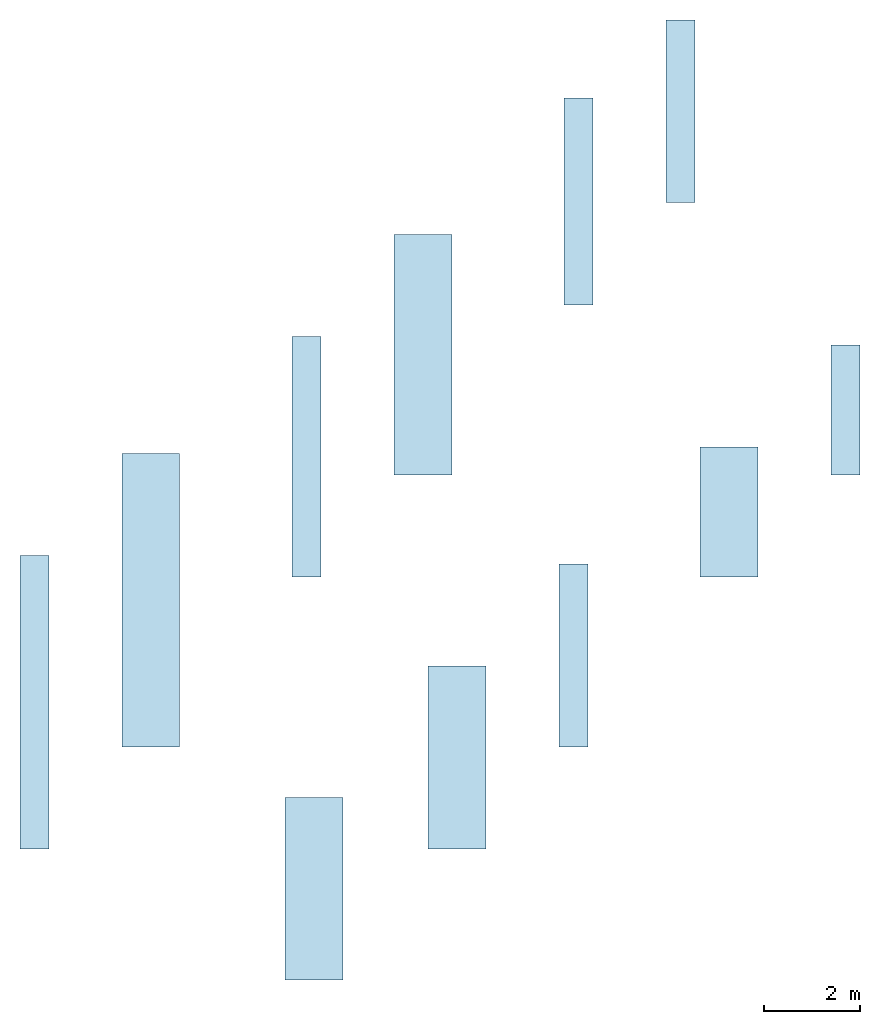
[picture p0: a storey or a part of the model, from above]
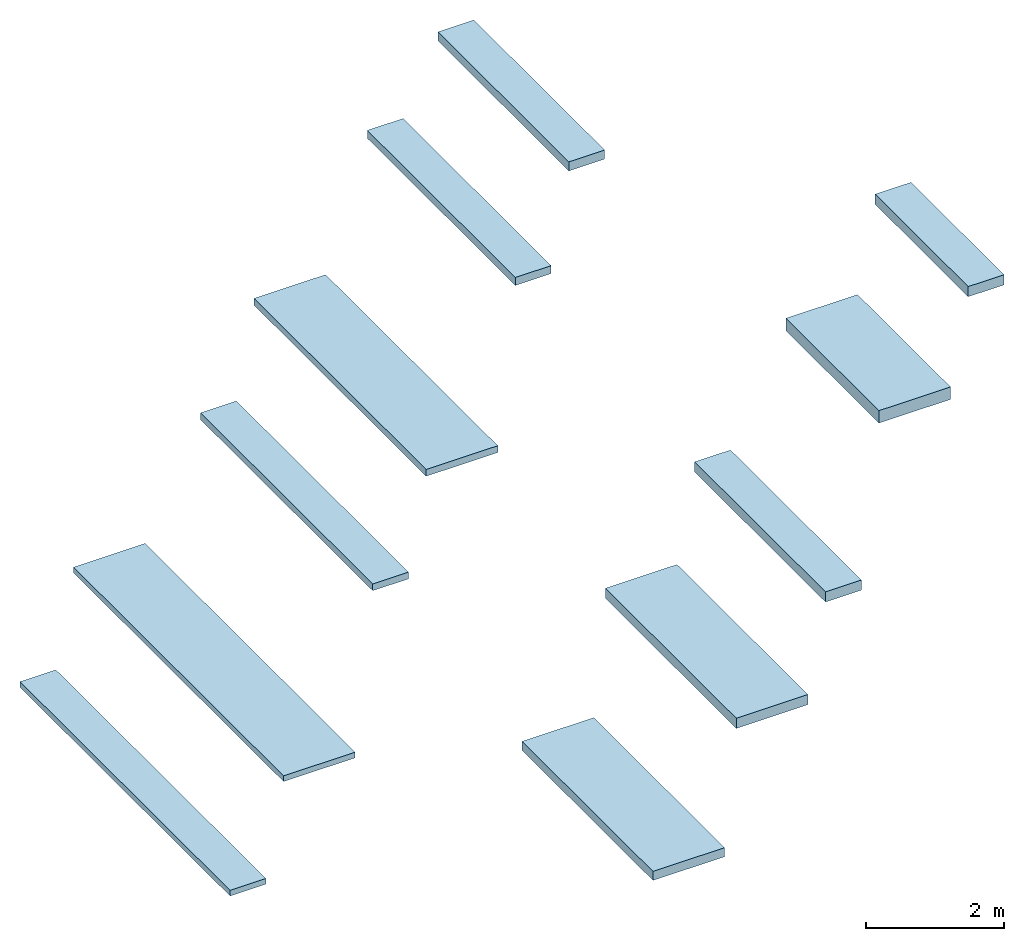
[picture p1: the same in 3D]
Properties of the parts of a building model (IFC2X3)

# File
Description: ViewDefinition [CoordinationView_V2.0, QuantityTakeOffAddOnView]
Time: 2021-05-19T20:16:23
Written by: The EXPRESS Data Manager Version 5.02.0100.07 : 28 Aug 2013
Made in: 20190108_1515(x64) - Exporter 19.1.0.0 - Alternate UI 19.1.0.0
Comment: STEP Physical File produced by: The EXPRESS Data Manager Version 5.02.0100.07 : 28 Aug 2013 * Module: EDMstepFileFactory/EDMstandAlone * Creation date: Wed May 19 20:16:23 2021 * Host: lt-026 * Database: C:\Users\WF2BF~1.POE\AppData\Local\Temp\{DC780830-4905-4681-B3EC-D57499B1AC45}\ifc * Database version: 5507 * Database creation date: Wed May 19 20:16:22 2021 * Schema: IFC2X3 * Model: DataRepository.ifc * Model creation date: Wed May 19 20:16:23 2021 * Header model: DataRepository.ifc_HeaderModel * Header model creation date: Wed May 19 20:16:23 2021 * EDMuser: sdai-user * EDMgroup: sdai-group * License ID and type: 5605 : Permanent license. Expiry date: * EDMstepFileFactory options: 020000

# IfcSite, Default
RefLatitude: 42, 24, 53, 508911; RefLongitude: -71, -15, -29, -58837; RefElevation: 0 mm
Other - Category: Project Information

# IfcBuilding
Pset_BuildingCommon - NumberOfStoreys: 1
Pset_ProductRequirements - Category: Project Information; sets with these values: 2

# IfcBuildingStorey: Level:Level 1, Level 1
LongName: Level 1; Elevation: 0 mm
Pset_AirSideSystemInformation - Name: Level 1
Pset_ProductRequirements - Name: Level 1; Category: Levels
Constraints - Elevation: 0 mm
Dimensions - Computation Height: 0 mm
Identity Data - Building Story: yes; Name: Level 1; Structural: no
Other - Category: Levels; Family: Level: Level 1; Family and Type: Level: Level 1; Type: Level: Level 1; Type Id: Level: Level 1
Constraints(Type) - Elevation Base: Project Base Point
Graphics(Type) - Color: 0; Line Pattern: Solid; Line Weight: 1; Symbol at End 1 Default: no; Symbol at End 2 Default: yes
Identity Data(Type) - Type Name: Level 1
Other(Type) - Category: Levels; Family Name: Level

# IfcRoof: Basic Roof:NLRS_27_RO_Mineral Wool 34 Alu Plus_100x1200x6100mm, Basic Roof:NLRS_27_RO_Mineral Wool 34 Alu Plus_100x1200x6100mm:4963
In: Level 1
Classification: 27 Daken (Uniformat)
Pset_ElementShading - Roughness: 304.8 mm
Pset_ManufacturerTypeInformation - Manufacturer: Knauf Insulation B.V.
Pset_ProductRequirements - Category: Roofs
Pset_QuantityTakeOff - Reference: NLRS_27_RO_Mineral Wool 34 Alu Plus_100x1200x6100mm
Pset_RoofCommon - IsExternal: yes; Reference: NLRS_27_RO_Mineral Wool 34 Alu Plus_100x1200x6100mm; ProjectedArea: 7.32 m2; TotalArea: 7.32 m2
Constraints - Base Level: Level: Level 1; Base Offset From Level: 0 mm; Cutoff Offset: 0 mm; Related to Mass: no; Room Bounding: yes
Construction - Fascia Depth: 0 mm; Rafter Cut: Plumb Cut; Maximum Ridge Height: 100 mm
Dimensions - Area: 7.32 m2; Thickness: 100 mm; Volume: 0.732 m3
Other - Category: Roofs; Family: Basic Roof: NLRS_27_RO_Mineral Wool 34 Alu Plus_100x1200x6100mm; Family and Type: Basic Roof: NLRS_27_RO_Mineral Wool 34 Alu Plus_100x1200x6100mm; Type: Basic Roof: NLRS_27_RO_Mineral Wool 34 Alu Plus_100x1200x6100mm; Type Id: Basic Roof: NLRS_27_RO_Mineral Wool 34 Alu Plus_100x1200x6100mm
Phasing - Phase Created: New Construction
Analytical Properties(Type) - Roughness: 1; Thermal mass: 0; Absorptance: 0.1; Heat Transfer Coefficient (U): 0.34; Thermal Resistance (R): 2.94118
Construction(Type) - Default Thickness: 100 mm
Graphics(Type) - Coarse Scale Fill Color: 0
Identity Data(Type) - Type Image: Raster image: MW 34 Alu Plus .jpg (2); Assembly Code: 27; Assembly Description: Daken; Description: Mineral Wool 34 Alu Plus - 100mm; Manufacturer: Knauf Insulation B.V.; Model: Mineral Wool 34 Alu Plus is een minerale woldeken met ECOSE® Technology, bekleed met een dampdichte Aluminium folie; Type Name: NLRS_27_RO_Mineral Wool 34 Alu Plus_100x1200x6100mm; URL: www.knaufinsulation.nl
Other(Type) - Category: Roofs; Family Name: Basic Roof

# IfcRoof: Basic Roof:NLRS_27_RO_Mineral Wool 34 Alu Plus_100x600x6100mm, Basic Roof:NLRS_27_RO_Mineral Wool 34 Alu Plus_100x600x6100mm:4934
In: Level 1
Classification: 27 Daken (Uniformat)
Pset_ElementShading - Roughness: 304.8 mm
Pset_ManufacturerTypeInformation - Manufacturer: Knauf Insulation B.V.
Pset_ProductRequirements - Category: Roofs
Pset_QuantityTakeOff - Reference: NLRS_27_RO_Mineral Wool 34 Alu Plus_100x600x6100mm
Pset_RoofCommon - Reference: NLRS_27_RO_Mineral Wool 34 Alu Plus_100x600x6100mm; IsExternal: yes; ProjectedArea: 3.66 m2; TotalArea: 3.66 m2
Constraints - Base Level: Level: Level 1; Base Offset From Level: 0 mm; Cutoff Offset: 0 mm; Related to Mass: no; Room Bounding: yes
Construction - Fascia Depth: 0 mm; Maximum Ridge Height: 100 mm; Rafter Cut: Plumb Cut
Dimensions - Area: 3.66 m2; Thickness: 100 mm; Volume: 0.366 m3
Other - Category: Roofs; Family: Basic Roof: NLRS_27_RO_Mineral Wool 34 Alu Plus_100x600x6100mm; Family and Type: Basic Roof: NLRS_27_RO_Mineral Wool 34 Alu Plus_100x600x6100mm; Type: Basic Roof: NLRS_27_RO_Mineral Wool 34 Alu Plus_100x600x6100mm; Type Id: Basic Roof: NLRS_27_RO_Mineral Wool 34 Alu Plus_100x600x6100mm
Phasing - Phase Created: New Construction
Analytical Properties(Type) - Absorptance: 0.1; Heat Transfer Coefficient (U): 0.34; Roughness: 1; Thermal mass: 0; Thermal Resistance (R): 2.94118
Construction(Type) - Default Thickness: 100 mm
Graphics(Type) - Coarse Scale Fill Color: 0
Identity Data(Type) - Assembly Code: 27; Assembly Description: Daken; Description: Mineral Wool 34 Alu Plus - 100mm; Manufacturer: Knauf Insulation B.V.; Model: Mineral Wool 34 Alu Plus is een minerale woldeken met ECOSE® Technology, bekleed met een dampdichte Aluminium folie; Type Image: Raster image: MW 34 Alu Plus .jpg (2); Type Name: NLRS_27_RO_Mineral Wool 34 Alu Plus_100x600x6100mm; URL: www.knaufinsulation.nl
Other(Type) - Category: Roofs; Family Name: Basic Roof

# IfcRoof: Basic Roof:NLRS_27_RO_Mineral Wool 34 Alu Plus_120x1200x5000mm, Basic Roof:NLRS_27_RO_Mineral Wool 34 Alu Plus_120x1200x5000mm:5133
In: Level 1
Classification: 27 Daken (Uniformat)
Pset_ElementShading - Roughness: 304.8 mm
Pset_ManufacturerTypeInformation - Manufacturer: Knauf Insulation B.V.
Pset_ProductRequirements - Category: Roofs
Pset_QuantityTakeOff - Reference: NLRS_27_RO_Mineral Wool 34 Alu Plus_120x1200x5000mm
Pset_RoofCommon - IsExternal: yes; Reference: NLRS_27_RO_Mineral Wool 34 Alu Plus_120x1200x5000mm; ProjectedArea: 6 m2; TotalArea: 6 m2
Constraints - Base Level: Level: Level 1; Base Offset From Level: 0 mm; Cutoff Offset: 0 mm; Related to Mass: no; Room Bounding: yes
Construction - Fascia Depth: 0 mm; Rafter Cut: Plumb Cut; Maximum Ridge Height: 120 mm
Dimensions - Area: 6 m2; Thickness: 120 mm; Volume: 0.72 m3
Other - Category: Roofs; Family: Basic Roof: NLRS_27_RO_Mineral Wool 34 Alu Plus_120x1200x5000mm; Family and Type: Basic Roof: NLRS_27_RO_Mineral Wool 34 Alu Plus_120x1200x5000mm; Type: Basic Roof: NLRS_27_RO_Mineral Wool 34 Alu Plus_120x1200x5000mm; Type Id: Basic Roof: NLRS_27_RO_Mineral Wool 34 Alu Plus_120x1200x5000mm
Phasing - Phase Created: New Construction
Analytical Properties(Type) - Roughness: 1; Thermal mass: 0; Absorptance: 0.1; Heat Transfer Coefficient (U): 0.283333; Thermal Resistance (R): 3.52941
Construction(Type) - Default Thickness: 120 mm
Graphics(Type) - Coarse Scale Fill Color: 0
Identity Data(Type) - Type Image: Raster image: MW 34 Alu Plus .jpg (2); Assembly Code: 27; Assembly Description: Daken; Description: Mineral Wool 34 Alu Plus - 120mm; Manufacturer: Knauf Insulation B.V.; Model: Mineral Wool 34 Alu Plus is een minerale woldeken met ECOSE® Technology, bekleed met een dampdichte Aluminium folie; Type Name: NLRS_27_RO_Mineral Wool 34 Alu Plus_120x1200x5000mm; URL: www.knaufinsulation.nl
Other(Type) - Category: Roofs; Family Name: Basic Roof

# IfcRoof: Basic Roof:NLRS_27_RO_Mineral Wool 34 Alu Plus_120x600x5000mm, Basic Roof:NLRS_27_RO_Mineral Wool 34 Alu Plus_120x600x5000mm:5124
In: Level 1
Classification: 27 Daken (Uniformat)
Pset_ElementShading - Roughness: 304.8 mm
Pset_ManufacturerTypeInformation - Manufacturer: Knauf Insulation B.V.
Pset_ProductRequirements - Category: Roofs
Pset_QuantityTakeOff - Reference: NLRS_27_RO_Mineral Wool 34 Alu Plus_120x600x5000mm
Pset_RoofCommon - IsExternal: yes; Reference: NLRS_27_RO_Mineral Wool 34 Alu Plus_120x600x5000mm; ProjectedArea: 3 m2; TotalArea: 3 m2
Constraints - Base Level: Level: Level 1; Base Offset From Level: 0 mm; Cutoff Offset: 0 mm; Related to Mass: no; Room Bounding: yes
Construction - Fascia Depth: 0 mm; Rafter Cut: Plumb Cut; Maximum Ridge Height: 120 mm
Dimensions - Area: 3 m2; Thickness: 120 mm; Volume: 0.36 m3
Other - Category: Roofs; Family: Basic Roof: NLRS_27_RO_Mineral Wool 34 Alu Plus_120x600x5000mm; Family and Type: Basic Roof: NLRS_27_RO_Mineral Wool 34 Alu Plus_120x600x5000mm; Type: Basic Roof: NLRS_27_RO_Mineral Wool 34 Alu Plus_120x600x5000mm; Type Id: Basic Roof: NLRS_27_RO_Mineral Wool 34 Alu Plus_120x600x5000mm
Phasing - Phase Created: New Construction
Analytical Properties(Type) - Roughness: 1; Thermal mass: 0; Absorptance: 0.1; Heat Transfer Coefficient (U): 0.283333; Thermal Resistance (R): 3.52941
Construction(Type) - Default Thickness: 120 mm
Graphics(Type) - Coarse Scale Fill Color: 0
Identity Data(Type) - Type Image: Raster image: MW 34 Alu Plus .jpg (2); Assembly Code: 27; Assembly Description: Daken; Description: Mineral Wool 34 Alu Plus - 120mm; Manufacturer: Knauf Insulation B.V.; Model: Mineral Wool 34 Alu Plus is een minerale woldeken met ECOSE® Technology, bekleed met een dampdichte Aluminium folie; Type Name: NLRS_27_RO_Mineral Wool 34 Alu Plus_120x600x5000mm; URL: www.knaufinsulation.nl
Other(Type) - Category: Roofs; Family Name: Basic Roof

# IfcRoof: Basic Roof:NLRS_27_RO_Mineral Wool 34 Alu Plus_140x600x4300mm, Basic Roof:NLRS_27_RO_Mineral Wool 34 Alu Plus_140x600x4300mm:5226
In: Level 1
Classification: 27 Daken (Uniformat)
Pset_ElementShading - Roughness: 304.8 mm
Pset_ManufacturerTypeInformation - Manufacturer: Knauf Insulation B.V.
Pset_ProductRequirements - Category: Roofs
Pset_QuantityTakeOff - Reference: NLRS_27_RO_Mineral Wool 34 Alu Plus_140x600x4300mm
Pset_RoofCommon - IsExternal: yes; Reference: NLRS_27_RO_Mineral Wool 34 Alu Plus_140x600x4300mm; ProjectedArea: 2.58 m2; TotalArea: 2.58 m2
Constraints - Base Level: Level: Level 1; Base Offset From Level: 0 mm; Cutoff Offset: 0 mm; Related to Mass: no; Room Bounding: yes
Construction - Fascia Depth: 0 mm; Rafter Cut: Plumb Cut; Maximum Ridge Height: 140 mm
Dimensions - Area: 2.58 m2; Thickness: 140 mm; Volume: 0.3612 m3
Other - Category: Roofs; Family: Basic Roof: NLRS_27_RO_Mineral Wool 34 Alu Plus_140x600x4300mm; Family and Type: Basic Roof: NLRS_27_RO_Mineral Wool 34 Alu Plus_140x600x4300mm; Type: Basic Roof: NLRS_27_RO_Mineral Wool 34 Alu Plus_140x600x4300mm; Type Id: Basic Roof: NLRS_27_RO_Mineral Wool 34 Alu Plus_140x600x4300mm
Phasing - Phase Created: New Construction
Analytical Properties(Type) - Roughness: 1; Thermal mass: 0; Absorptance: 0.1; Heat Transfer Coefficient (U): 0.242857; Thermal Resistance (R): 4.11765
Construction(Type) - Default Thickness: 140 mm
Graphics(Type) - Coarse Scale Fill Color: 0
Identity Data(Type) - Type Image: Raster image: MW 34 Alu Plus .jpg (2); Assembly Code: 27; Assembly Description: Daken; Description: Mineral Wool 34 Alu Plus - 140mm; Manufacturer: Knauf Insulation B.V.; Model: Mineral Wool 34 Alu Plus is een minerale woldeken met ECOSE® Technology, bekleed met een dampdichte Aluminium folie; Type Name: NLRS_27_RO_Mineral Wool 34 Alu Plus_140x600x4300mm; URL: www.knaufinsulation.nl
Other(Type) - Category: Roofs; Family Name: Basic Roof

# IfcRoof: Basic Roof:NLRS_27_RO_Mineral Wool 34 Alu Plus_160x1200x3800mm, Basic Roof:NLRS_27_RO_Mineral Wool 34 Alu Plus_160x1200x3800mm:6059
In: Level 1
Classification: 27 Daken (Uniformat)
Pset_ElementShading - Roughness: 304.8 mm
Pset_ManufacturerTypeInformation - Manufacturer: Knauf Insulation B.V.
Pset_ProductRequirements - Category: Roofs
Pset_QuantityTakeOff - Reference: NLRS_27_RO_Mineral Wool 34 Alu Plus_160x1200x3800mm
Pset_RoofCommon - IsExternal: yes; Reference: NLRS_27_RO_Mineral Wool 34 Alu Plus_160x1200x3800mm; ProjectedArea: 4.56 m2; TotalArea: 4.56 m2
Constraints - Base Level: Level: Level 1; Base Offset From Level: 0 mm; Cutoff Offset: 0 mm; Related to Mass: no; Room Bounding: yes
Construction - Fascia Depth: 0 mm; Rafter Cut: Plumb Cut; Maximum Ridge Height: 160 mm
Dimensions - Area: 4.56 m2; Thickness: 160 mm; Volume: 0.7296 m3
Other - Category: Roofs; Family: Basic Roof: NLRS_27_RO_Mineral Wool 34 Alu Plus_160x1200x3800mm; Family and Type: Basic Roof: NLRS_27_RO_Mineral Wool 34 Alu Plus_160x1200x3800mm; Type: Basic Roof: NLRS_27_RO_Mineral Wool 34 Alu Plus_160x1200x3800mm; Type Id: Basic Roof: NLRS_27_RO_Mineral Wool 34 Alu Plus_160x1200x3800mm
Phasing - Phase Created: New Construction
Analytical Properties(Type) - Roughness: 1; Thermal mass: 0; Absorptance: 0.1; Heat Transfer Coefficient (U): 0.2125; Thermal Resistance (R): 4.70588
Construction(Type) - Default Thickness: 160 mm
Graphics(Type) - Coarse Scale Fill Color: 0
Identity Data(Type) - Type Image: Raster image: MW 34 Alu Plus .jpg (2); Assembly Code: 27; Assembly Description: Daken; Description: Mineral Wool 34 Alu Plus - 160mm; Manufacturer: Knauf Insulation B.V.; Model: Mineral Wool 34 Alu Plus is een minerale woldeken met ECOSE® Technology, bekleed met een dampdichte Aluminium folie; Type Name: NLRS_27_RO_Mineral Wool 34 Alu Plus_160x1200x3800mm; URL: www.knaufinsulation.nl
Other(Type) - Category: Roofs; Family Name: Basic Roof

# IfcRoof: Basic Roof:NLRS_27_RO_Mineral Wool 34 Alu Plus_160x600x3800mm, Basic Roof:NLRS_27_RO_Mineral Wool 34 Alu Plus_160x600x3800mm:5233
In: Level 1
Classification: 27 Daken (Uniformat)
Pset_ElementShading - Roughness: 304.8 mm
Pset_ManufacturerTypeInformation - Manufacturer: Knauf Insulation B.V.
Pset_ProductRequirements - Category: Roofs
Pset_QuantityTakeOff - Reference: NLRS_27_RO_Mineral Wool 34 Alu Plus_160x600x3800mm
Pset_RoofCommon - IsExternal: yes; Reference: NLRS_27_RO_Mineral Wool 34 Alu Plus_160x600x3800mm; ProjectedArea: 2.28 m2; TotalArea: 2.28 m2
Constraints - Base Level: Level: Level 1; Base Offset From Level: 0 mm; Cutoff Offset: 0 mm; Related to Mass: no; Room Bounding: yes
Construction - Fascia Depth: 0 mm; Rafter Cut: Plumb Cut; Maximum Ridge Height: 160 mm
Dimensions - Area: 2.28 m2; Thickness: 160 mm; Volume: 0.3648 m3
Other - Category: Roofs; Family: Basic Roof: NLRS_27_RO_Mineral Wool 34 Alu Plus_160x600x3800mm; Family and Type: Basic Roof: NLRS_27_RO_Mineral Wool 34 Alu Plus_160x600x3800mm; Type: Basic Roof: NLRS_27_RO_Mineral Wool 34 Alu Plus_160x600x3800mm; Type Id: Basic Roof: NLRS_27_RO_Mineral Wool 34 Alu Plus_160x600x3800mm
Phasing - Phase Created: New Construction
Analytical Properties(Type) - Roughness: 1; Thermal mass: 0; Absorptance: 0.1; Heat Transfer Coefficient (U): 0.2125; Thermal Resistance (R): 4.70588
Construction(Type) - Default Thickness: 160 mm
Graphics(Type) - Coarse Scale Fill Color: 0
Identity Data(Type) - Type Image: Raster image: MW 34 Alu Plus .jpg (2); Assembly Code: 27; Assembly Description: Daken; Description: Mineral Wool 34 Alu Plus - 160mm; Manufacturer: Knauf Insulation B.V.; Model: Mineral Wool 34 Alu Plus is een minerale woldeken met ECOSE® Technology, bekleed met een dampdichte Aluminium folie; Type Name: NLRS_27_RO_Mineral Wool 34 Alu Plus_160x600x3800mm; URL: www.knaufinsulation.nl
Other(Type) - Category: Roofs; Family Name: Basic Roof

# IfcRoof: Basic Roof:NLRS_27_RO_Mineral Wool 34 Alu Plus_180x1200x3400mm, Basic Roof:NLRS_27_RO_Mineral Wool 34 Alu Plus_180x1200x3400mm:5939
In: Level 1
Classification: 27 Daken (Uniformat)
Pset_ElementShading - Roughness: 304.8 mm
Pset_ManufacturerTypeInformation - Manufacturer: Knauf Insulation B.V.
Pset_ProductRequirements - Category: Roofs
Pset_QuantityTakeOff - Reference: NLRS_27_RO_Mineral Wool 34 Alu Plus_180x1200x3400mm
Pset_RoofCommon - IsExternal: yes; Reference: NLRS_27_RO_Mineral Wool 34 Alu Plus_180x1200x3400mm; ProjectedArea: 4.56 m2; TotalArea: 4.56 m2
Constraints - Base Level: Level: Level 1; Base Offset From Level: 0 mm; Cutoff Offset: 0 mm; Related to Mass: no; Room Bounding: yes
Construction - Fascia Depth: 0 mm; Rafter Cut: Plumb Cut; Maximum Ridge Height: 180 mm
Dimensions - Area: 4.56 m2; Thickness: 180 mm; Volume: 0.8208 m3
Other - Category: Roofs; Family: Basic Roof: NLRS_27_RO_Mineral Wool 34 Alu Plus_180x1200x3400mm; Family and Type: Basic Roof: NLRS_27_RO_Mineral Wool 34 Alu Plus_180x1200x3400mm; Type: Basic Roof: NLRS_27_RO_Mineral Wool 34 Alu Plus_180x1200x3400mm; Type Id: Basic Roof: NLRS_27_RO_Mineral Wool 34 Alu Plus_180x1200x3400mm
Phasing - Phase Created: New Construction
Analytical Properties(Type) - Roughness: 1; Thermal mass: 0; Absorptance: 0.1; Heat Transfer Coefficient (U): 0.188889; Thermal Resistance (R): 5.29412
Construction(Type) - Default Thickness: 180 mm
Graphics(Type) - Coarse Scale Fill Color: 0
Identity Data(Type) - Type Image: Raster image: MW 34 Alu Plus .jpg (2); Assembly Code: 27; Assembly Description: Daken; Description: Mineral Wool 34 Alu Plus - 180mm; Manufacturer: Knauf Insulation B.V.; Model: Mineral Wool 34 Alu Plus is een minerale woldeken met ECOSE® Technology, bekleed met een dampdichte Aluminium folie; Type Name: NLRS_27_RO_Mineral Wool 34 Alu Plus_180x1200x3400mm; URL: www.knaufinsulation.nl
Other(Type) - Category: Roofs; Family Name: Basic Roof

# IfcRoof: Basic Roof:NLRS_27_RO_Mineral Wool 34 Alu Plus_180x600x3400mm, Basic Roof:NLRS_27_RO_Mineral Wool 34 Alu Plus_180x600x3400mm:6156
In: Level 1
Classification: 27 Daken (Uniformat)
Pset_ElementShading - Roughness: 304.8 mm
Pset_ManufacturerTypeInformation - Manufacturer: Knauf Insulation B.V.
Pset_ProductRequirements - Category: Roofs
Pset_QuantityTakeOff - Reference: NLRS_27_RO_Mineral Wool 34 Alu Plus_180x600x3400mm
Pset_RoofCommon - IsExternal: yes; Reference: NLRS_27_RO_Mineral Wool 34 Alu Plus_180x600x3400mm; ProjectedArea: 2.28 m2; TotalArea: 2.28 m2
Constraints - Base Level: Level: Level 1; Base Offset From Level: 0 mm; Cutoff Offset: 0 mm; Related to Mass: no; Room Bounding: yes
Construction - Fascia Depth: 0 mm; Rafter Cut: Plumb Cut; Maximum Ridge Height: 180 mm
Dimensions - Area: 2.28 m2; Thickness: 180 mm; Volume: 0.4104 m3
Other - Category: Roofs; Family: Basic Roof: NLRS_27_RO_Mineral Wool 34 Alu Plus_180x600x3400mm; Family and Type: Basic Roof: NLRS_27_RO_Mineral Wool 34 Alu Plus_180x600x3400mm; Type: Basic Roof: NLRS_27_RO_Mineral Wool 34 Alu Plus_180x600x3400mm; Type Id: Basic Roof: NLRS_27_RO_Mineral Wool 34 Alu Plus_180x600x3400mm
Phasing - Phase Created: New Construction
Analytical Properties(Type) - Roughness: 1; Thermal mass: 0; Absorptance: 0.1; Heat Transfer Coefficient (U): 0.188889; Thermal Resistance (R): 5.29412
Construction(Type) - Default Thickness: 180 mm
Graphics(Type) - Coarse Scale Fill Color: 0
Identity Data(Type) - Type Image: Raster image: MW 34 Alu Plus .jpg (2); Assembly Code: 27; Assembly Description: Daken; Description: Mineral Wool 34 Alu Plus - 180mm; Manufacturer: Knauf Insulation B.V.; Model: Mineral Wool 34 Alu Plus is een minerale woldeken met ECOSE® Technology, bekleed met een dampdichte Aluminium folie; Type Name: NLRS_27_RO_Mineral Wool 34 Alu Plus_180x600x3400mm; URL: www.knaufinsulation.nl
Other(Type) - Category: Roofs; Family Name: Basic Roof

# IfcRoof: Basic Roof:NLRS_27_RO_Mineral Wool 34 Alu Plus_220x1200x2700mm, Basic Roof:NLRS_27_RO_Mineral Wool 34 Alu Plus_220x1200x2700mm:6230
In: Level 1
Classification: 27 Daken (Uniformat)
Pset_ElementShading - Roughness: 304.8 mm
Pset_ManufacturerTypeInformation - Manufacturer: Knauf Insulation B.V.
Pset_ProductRequirements - Category: Roofs
Pset_QuantityTakeOff - Reference: NLRS_27_RO_Mineral Wool 34 Alu Plus_220x1200x2700mm
Pset_RoofCommon - IsExternal: yes; Reference: NLRS_27_RO_Mineral Wool 34 Alu Plus_220x1200x2700mm; ProjectedArea: 3.24 m2; TotalArea: 3.24 m2
Constraints - Base Level: Level: Level 1; Base Offset From Level: 0 mm; Cutoff Offset: 0 mm; Related to Mass: no; Room Bounding: yes
Construction - Fascia Depth: 0 mm; Rafter Cut: Plumb Cut; Maximum Ridge Height: 220 mm
Dimensions - Area: 3.24 m2; Thickness: 220 mm; Volume: 0.7128 m3
Other - Category: Roofs; Family: Basic Roof: NLRS_27_RO_Mineral Wool 34 Alu Plus_220x1200x2700mm; Family and Type: Basic Roof: NLRS_27_RO_Mineral Wool 34 Alu Plus_220x1200x2700mm; Type: Basic Roof: NLRS_27_RO_Mineral Wool 34 Alu Plus_220x1200x2700mm; Type Id: Basic Roof: NLRS_27_RO_Mineral Wool 34 Alu Plus_220x1200x2700mm
Phasing - Phase Created: New Construction
Analytical Properties(Type) - Roughness: 1; Thermal mass: 0; Absorptance: 0.1; Heat Transfer Coefficient (U): 0.154545; Thermal Resistance (R): 6.47059
Construction(Type) - Default Thickness: 220 mm
Graphics(Type) - Coarse Scale Fill Color: 0
Identity Data(Type) - Type Image: Raster image: MW 34 Alu Plus .jpg (2); Assembly Code: 27; Assembly Description: Daken; Description: Mineral Wool 34 Alu Plus - 220mm; Manufacturer: Knauf Insulation B.V.; Model: Mineral Wool 34 Alu Plus is een minerale woldeken met ECOSE® Technology, bekleed met een dampdichte Aluminium folie; Type Name: NLRS_27_RO_Mineral Wool 34 Alu Plus_220x1200x2700mm; URL: www.knaufinsulation.nl
Other(Type) - Category: Roofs; Family Name: Basic Roof

# IfcRoof: Basic Roof:NLRS_27_RO_Mineral Wool 34 Alu Plus_220x600x2700mm, Basic Roof:NLRS_27_RO_Mineral Wool 34 Alu Plus_220x600x2700mm:6239
In: Level 1
Classification: 27 Daken (Uniformat)
Pset_ElementShading - Roughness: 304.8 mm
Pset_ManufacturerTypeInformation - Manufacturer: Knauf Insulation B.V.
Pset_ProductRequirements - Category: Roofs
Pset_QuantityTakeOff - Reference: NLRS_27_RO_Mineral Wool 34 Alu Plus_220x600x2700mm
Pset_RoofCommon - IsExternal: yes; Reference: NLRS_27_RO_Mineral Wool 34 Alu Plus_220x600x2700mm; ProjectedArea: 1.62 m2; TotalArea: 1.62 m2
Constraints - Base Level: Level: Level 1; Base Offset From Level: 0 mm; Cutoff Offset: 0 mm; Related to Mass: no; Room Bounding: yes
Construction - Fascia Depth: 0 mm; Rafter Cut: Plumb Cut; Maximum Ridge Height: 180 mm
Dimensions - Area: 1.62 m2; Thickness: 180 mm; Volume: 0.2916 m3
Other - Category: Roofs; Family: Basic Roof: NLRS_27_RO_Mineral Wool 34 Alu Plus_220x600x2700mm; Family and Type: Basic Roof: NLRS_27_RO_Mineral Wool 34 Alu Plus_220x600x2700mm; Type: Basic Roof: NLRS_27_RO_Mineral Wool 34 Alu Plus_220x600x2700mm; Type Id: Basic Roof: NLRS_27_RO_Mineral Wool 34 Alu Plus_220x600x2700mm
Phasing - Phase Created: New Construction
Analytical Properties(Type) - Roughness: 1; Thermal mass: 0; Absorptance: 0.1; Heat Transfer Coefficient (U): 0.188889; Thermal Resistance (R): 5.29412
Construction(Type) - Default Thickness: 180 mm
Graphics(Type) - Coarse Scale Fill Color: 0
Identity Data(Type) - Type Image: Raster image: MW 34 Alu Plus .jpg (2); Assembly Code: 27; Assembly Description: Daken; Description: Mineral Wool 34 Alu Plus - 220mm; Manufacturer: Knauf Insulation B.V.; Model: Mineral Wool 34 Alu Plus is een minerale woldeken met ECOSE® Technology, bekleed met een dampdichte Aluminium folie; Type Name: NLRS_27_RO_Mineral Wool 34 Alu Plus_220x600x2700mm; URL: www.knaufinsulation.nl
Other(Type) - Category: Roofs; Family Name: Basic Roof

# IfcSlab: Basic Roof:NLRS_27_RO_Mineral Wool 34 Alu Plus_100x1200x6100mm, Basic Roof:NLRS_27_RO_Mineral Wool 34 Alu Plus_100x1200x6100mm:4963
In: Level 1
PredefinedType: ROOF; Classification: 27 Daken (Uniformat); Material: Knauf Insulation_Mineral Wool 34 Alu Plus Ecose®minerale wol 100 mm
Pset_ElementShading - Roughness: 304.8 mm
Pset_ManufacturerTypeInformation - Manufacturer: Knauf Insulation B.V.
Pset_ProductRequirements - Category: Roofs
Pset_QuantityTakeOff - Reference: NLRS_27_RO_Mineral Wool 34 Alu Plus_100x1200x6100mm
Pset_ReinforcementBarPitchOfSlab - Description: Mineral Wool 34 Alu Plus - 100mm; Reference: NLRS_27_RO_Mineral Wool 34 Alu Plus_100x1200x6100mm
Pset_SlabCommon - IsExternal: yes; PitchAngle: 0 deg; Reference: NLRS_27_RO_Mineral Wool 34 Alu Plus_100x1200x6100mm; ThermalTransmittance: 0.34 kg/K/s3
BaseQuantities - GrossArea: 0.68005 m2; NetArea: 16.1 m2; GrossVolume: 68.005 m3; NetVolume: 0.732 m3; Perimeter: 14600 mm; Width: 100 mm

# IfcSlab: Basic Roof:NLRS_27_RO_Mineral Wool 34 Alu Plus_100x600x6100mm, Basic Roof:NLRS_27_RO_Mineral Wool 34 Alu Plus_100x600x6100mm:4934
In: Level 1
PredefinedType: ROOF; Classification: 27 Daken (Uniformat); Material: Knauf Insulation_Mineral Wool 34 Alu Plus Ecose®minerale wol 100 mm
Pset_ElementShading - Roughness: 304.8 mm
Pset_ManufacturerTypeInformation - Manufacturer: Knauf Insulation B.V.
Pset_ProductRequirements - Category: Roofs
Pset_QuantityTakeOff - Reference: NLRS_27_RO_Mineral Wool 34 Alu Plus_100x600x6100mm
Pset_ReinforcementBarPitchOfSlab - Description: Mineral Wool 34 Alu Plus - 100mm; Reference: NLRS_27_RO_Mineral Wool 34 Alu Plus_100x600x6100mm
Pset_SlabCommon - Reference: NLRS_27_RO_Mineral Wool 34 Alu Plus_100x600x6100mm; IsExternal: yes; ThermalTransmittance: 0.34 kg/K/s3; PitchAngle: 0 deg
BaseQuantities - GrossArea: 0.340025 m2; NetArea: 8.66 m2; GrossVolume: 34.0025 m3; NetVolume: 0.366 m3; Perimeter: 13400 mm; Width: 100 mm

# IfcSlab: Basic Roof:NLRS_27_RO_Mineral Wool 34 Alu Plus_120x1200x5000mm, Basic Roof:NLRS_27_RO_Mineral Wool 34 Alu Plus_120x1200x5000mm:5133
In: Level 1
PredefinedType: ROOF; Classification: 27 Daken (Uniformat); Material: Knauf Insulation_Mineral Wool 34 Alu Plus Ecose®minerale wol 120 mm
Pset_ElementShading - Roughness: 304.8 mm
Pset_ManufacturerTypeInformation - Manufacturer: Knauf Insulation B.V.
Pset_ProductRequirements - Category: Roofs
Pset_QuantityTakeOff - Reference: NLRS_27_RO_Mineral Wool 34 Alu Plus_120x1200x5000mm
Pset_ReinforcementBarPitchOfSlab - Description: Mineral Wool 34 Alu Plus - 120mm; Reference: NLRS_27_RO_Mineral Wool 34 Alu Plus_120x1200x5000mm
Pset_SlabCommon - IsExternal: yes; PitchAngle: 0 deg; Reference: NLRS_27_RO_Mineral Wool 34 Alu Plus_120x1200x5000mm; ThermalTransmittance: 0.283333 kg/K/s3
BaseQuantities - GrossArea: 0.557418 m2; NetArea: 13.488 m2; GrossVolume: 66.8902 m3; NetVolume: 0.72 m3; Perimeter: 12400 mm; Width: 120 mm

# IfcSlab: Basic Roof:NLRS_27_RO_Mineral Wool 34 Alu Plus_120x600x5000mm, Basic Roof:NLRS_27_RO_Mineral Wool 34 Alu Plus_120x600x5000mm:5124
In: Level 1
PredefinedType: ROOF; Classification: 27 Daken (Uniformat); Material: Knauf Insulation_Mineral Wool 34 Alu Plus Ecose®minerale wol 120 mm
Pset_ElementShading - Roughness: 304.8 mm
Pset_ManufacturerTypeInformation - Manufacturer: Knauf Insulation B.V.
Pset_ProductRequirements - Category: Roofs
Pset_QuantityTakeOff - Reference: NLRS_27_RO_Mineral Wool 34 Alu Plus_120x600x5000mm
Pset_ReinforcementBarPitchOfSlab - Description: Mineral Wool 34 Alu Plus - 120mm; Reference: NLRS_27_RO_Mineral Wool 34 Alu Plus_120x600x5000mm
Pset_SlabCommon - IsExternal: yes; PitchAngle: 0 deg; Reference: NLRS_27_RO_Mineral Wool 34 Alu Plus_120x600x5000mm; ThermalTransmittance: 0.283333 kg/K/s3
BaseQuantities - GrossArea: 0.278709 m2; NetArea: 7.344 m2; GrossVolume: 33.4451 m3; NetVolume: 0.36 m3; Perimeter: 11200 mm; Width: 120 mm

# IfcSlab: Basic Roof:NLRS_27_RO_Mineral Wool 34 Alu Plus_140x600x4300mm, Basic Roof:NLRS_27_RO_Mineral Wool 34 Alu Plus_140x600x4300mm:5226
In: Level 1
PredefinedType: ROOF; Classification: 27 Daken (Uniformat); Material: Knauf Insulation_Mineral Wool 34 Alu Plus Ecose®minerale wol 140 mm
Pset_ElementShading - Roughness: 304.8 mm
Pset_ManufacturerTypeInformation - Manufacturer: Knauf Insulation B.V.
Pset_ProductRequirements - Category: Roofs
Pset_QuantityTakeOff - Reference: NLRS_27_RO_Mineral Wool 34 Alu Plus_140x600x4300mm
Pset_ReinforcementBarPitchOfSlab - Description: Mineral Wool 34 Alu Plus - 140mm; Reference: NLRS_27_RO_Mineral Wool 34 Alu Plus_140x600x4300mm
Pset_SlabCommon - IsExternal: yes; PitchAngle: 0 deg; Reference: NLRS_27_RO_Mineral Wool 34 Alu Plus_140x600x4300mm; ThermalTransmittance: 0.242857 kg/K/s3
BaseQuantities - GrossArea: 0.23969 m2; NetArea: 6.532 m2; GrossVolume: 33.5566 m3; NetVolume: 0.3612 m3; Perimeter: 9800 mm; Width: 140 mm

# IfcSlab: Basic Roof:NLRS_27_RO_Mineral Wool 34 Alu Plus_160x1200x3800mm, Basic Roof:NLRS_27_RO_Mineral Wool 34 Alu Plus_160x1200x3800mm:6059
In: Level 1
PredefinedType: ROOF; Classification: 27 Daken (Uniformat); Material: Knauf Insulation_Mineral Wool 34 Alu Plus Ecose®minerale wol 160 mm
Pset_ElementShading - Roughness: 304.8 mm
Pset_ManufacturerTypeInformation - Manufacturer: Knauf Insulation B.V.
Pset_ProductRequirements - Category: Roofs
Pset_QuantityTakeOff - Reference: NLRS_27_RO_Mineral Wool 34 Alu Plus_160x1200x3800mm
Pset_ReinforcementBarPitchOfSlab - Description: Mineral Wool 34 Alu Plus - 160mm; Reference: NLRS_27_RO_Mineral Wool 34 Alu Plus_160x1200x3800mm
Pset_SlabCommon - IsExternal: yes; PitchAngle: 0 deg; Reference: NLRS_27_RO_Mineral Wool 34 Alu Plus_160x1200x3800mm; ThermalTransmittance: 0.2125 kg/K/s3
BaseQuantities - GrossArea: 0.423638 m2; NetArea: 10.72 m2; GrossVolume: 67.7821 m3; NetVolume: 0.7296 m3; Perimeter: 10000 mm; Width: 160 mm

# IfcSlab: Basic Roof:NLRS_27_RO_Mineral Wool 34 Alu Plus_160x600x3800mm, Basic Roof:NLRS_27_RO_Mineral Wool 34 Alu Plus_160x600x3800mm:5233
In: Level 1
PredefinedType: ROOF; Classification: 27 Daken (Uniformat); Material: Knauf Insulation_Mineral Wool 34 Alu Plus Ecose®minerale wol 160 mm
Pset_ElementShading - Roughness: 304.8 mm
Pset_ManufacturerTypeInformation - Manufacturer: Knauf Insulation B.V.
Pset_ProductRequirements - Category: Roofs
Pset_QuantityTakeOff - Reference: NLRS_27_RO_Mineral Wool 34 Alu Plus_160x600x3800mm
Pset_ReinforcementBarPitchOfSlab - Description: Mineral Wool 34 Alu Plus - 160mm; Reference: NLRS_27_RO_Mineral Wool 34 Alu Plus_160x600x3800mm
Pset_SlabCommon - IsExternal: yes; PitchAngle: 0 deg; Reference: NLRS_27_RO_Mineral Wool 34 Alu Plus_160x600x3800mm; ThermalTransmittance: 0.2125 kg/K/s3
BaseQuantities - GrossArea: 0.211819 m2; NetArea: 5.968 m2; GrossVolume: 33.891 m3; NetVolume: 0.3648 m3; Perimeter: 8800 mm; Width: 160 mm

# IfcSlab: Basic Roof:NLRS_27_RO_Mineral Wool 34 Alu Plus_180x1200x3400mm, Basic Roof:NLRS_27_RO_Mineral Wool 34 Alu Plus_180x1200x3400mm:5939
In: Level 1
PredefinedType: ROOF; Classification: 27 Daken (Uniformat); Material: Knauf Insulation_Mineral Wool 34 Alu Plus Ecose®minerale wol 180 mm
Pset_ElementShading - Roughness: 304.8 mm
Pset_ManufacturerTypeInformation - Manufacturer: Knauf Insulation B.V.
Pset_ProductRequirements - Category: Roofs
Pset_QuantityTakeOff - Reference: NLRS_27_RO_Mineral Wool 34 Alu Plus_180x1200x3400mm
Pset_ReinforcementBarPitchOfSlab - Description: Mineral Wool 34 Alu Plus - 180mm; Reference: NLRS_27_RO_Mineral Wool 34 Alu Plus_180x1200x3400mm
Pset_SlabCommon - IsExternal: yes; PitchAngle: 0 deg; Reference: NLRS_27_RO_Mineral Wool 34 Alu Plus_180x1200x3400mm; ThermalTransmittance: 0.188889 kg/K/s3
BaseQuantities - GrossArea: 0.423638 m2; NetArea: 10.92 m2; GrossVolume: 76.2548 m3; NetVolume: 0.8208 m3; Perimeter: 10000 mm; Width: 180 mm

# IfcSlab: Basic Roof:NLRS_27_RO_Mineral Wool 34 Alu Plus_180x600x3400mm, Basic Roof:NLRS_27_RO_Mineral Wool 34 Alu Plus_180x600x3400mm:6156
In: Level 1
PredefinedType: ROOF; Classification: 27 Daken (Uniformat); Material: Knauf Insulation_Mineral Wool 34 Alu Plus Ecose®minerale wol 180 mm
Pset_ElementShading - Roughness: 304.8 mm
Pset_ManufacturerTypeInformation - Manufacturer: Knauf Insulation B.V.
Pset_ProductRequirements - Category: Roofs
Pset_QuantityTakeOff - Reference: NLRS_27_RO_Mineral Wool 34 Alu Plus_180x600x3400mm
Pset_ReinforcementBarPitchOfSlab - Description: Mineral Wool 34 Alu Plus - 180mm; Reference: NLRS_27_RO_Mineral Wool 34 Alu Plus_180x600x3400mm
Pset_SlabCommon - IsExternal: yes; PitchAngle: 0 deg; Reference: NLRS_27_RO_Mineral Wool 34 Alu Plus_180x600x3400mm; ThermalTransmittance: 0.188889 kg/K/s3
BaseQuantities - GrossArea: 0.211819 m2; NetArea: 6.144 m2; GrossVolume: 38.1274 m3; NetVolume: 0.4104 m3; Perimeter: 8800 mm; Width: 180 mm

# IfcSlab: Basic Roof:NLRS_27_RO_Mineral Wool 34 Alu Plus_220x1200x2700mm, Basic Roof:NLRS_27_RO_Mineral Wool 34 Alu Plus_220x1200x2700mm:6230
In: Level 1
PredefinedType: ROOF; Classification: 27 Daken (Uniformat); Material: Knauf Insulation_Mineral Wool 34 Alu Plus Ecose®minerale wol 220 mm
Pset_ElementShading - Roughness: 304.8 mm
Pset_ManufacturerTypeInformation - Manufacturer: Knauf Insulation B.V.
Pset_ProductRequirements - Category: Roofs
Pset_QuantityTakeOff - Reference: NLRS_27_RO_Mineral Wool 34 Alu Plus_220x1200x2700mm
Pset_ReinforcementBarPitchOfSlab - Description: Mineral Wool 34 Alu Plus - 220mm; Reference: NLRS_27_RO_Mineral Wool 34 Alu Plus_220x1200x2700mm
Pset_SlabCommon - IsExternal: yes; PitchAngle: 0 deg; Reference: NLRS_27_RO_Mineral Wool 34 Alu Plus_220x1200x2700mm; ThermalTransmittance: 0.154545 kg/K/s3
BaseQuantities - GrossArea: 0.301006 m2; NetArea: 8.196 m2; GrossVolume: 66.2213 m3; NetVolume: 0.7128 m3; Perimeter: 7800 mm; Width: 220 mm

# IfcSlab: Basic Roof:NLRS_27_RO_Mineral Wool 34 Alu Plus_220x600x2700mm, Basic Roof:NLRS_27_RO_Mineral Wool 34 Alu Plus_220x600x2700mm:6239
In: Level 1
PredefinedType: ROOF; Classification: 27 Daken (Uniformat); Material: Knauf Insulation_Mineral Wool 34 Alu Plus Ecose®minerale wol 180 mm
Pset_ElementShading - Roughness: 304.8 mm
Pset_ManufacturerTypeInformation - Manufacturer: Knauf Insulation B.V.
Pset_ProductRequirements - Category: Roofs
Pset_QuantityTakeOff - Reference: NLRS_27_RO_Mineral Wool 34 Alu Plus_220x600x2700mm
Pset_ReinforcementBarPitchOfSlab - Description: Mineral Wool 34 Alu Plus - 220mm; Reference: NLRS_27_RO_Mineral Wool 34 Alu Plus_220x600x2700mm
Pset_SlabCommon - IsExternal: yes; PitchAngle: 0 deg; Reference: NLRS_27_RO_Mineral Wool 34 Alu Plus_220x600x2700mm; ThermalTransmittance: 0.188889 kg/K/s3
BaseQuantities - GrossArea: 0.150503 m2; NetArea: 4.428 m2; GrossVolume: 27.0905 m3; NetVolume: 0.2916 m3; Perimeter: 6600 mm; Width: 180 mm
